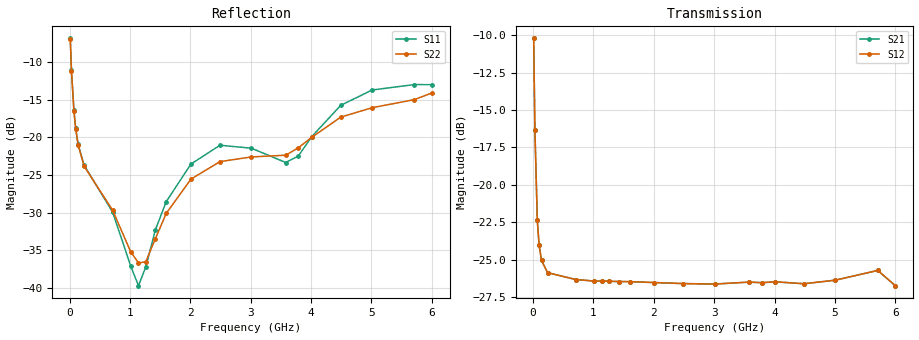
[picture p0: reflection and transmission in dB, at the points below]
! Integrated Device Technology
! Corporate Headquarters
! 6024 Silver Creek Valley Road
! San Jose, CA 95138  USA
! Phone:  1-408-284-8200
! Toll Free:  1-800-223-1366
! Webpage:  http://www.idt.com/
! Timing and RF Division
! 515 Groton Road, Suite 102
! Westford, MA 01886-6024
! Device:  F1951
! Description: 6-bit 0.5 dB Digital Step Attenuator
! Frequency:  100.0 -  4000.00 MHz
! Package:  4x4 mm Thin QFN Plastic Package: 24 pin
! Ports:  2 RF, 6 DC
!  Pin  1  = NC
!  Pin  2  = RF1  =  Port 1
!  Pin  3  = GND
!  Pin  4  = NC
!  Pin  5  = Serial Data Out (SDO)
!  Pin  6  = NC
!  Pin  7  = Reset Bar ( RSTb)
!  Pin  8  = Clock (CLK)
!  Pin  9  = Chip Select Bar (CSb)
!  Pin 10  = NC
!  Pin 11  = Serial Data In (SDI)
!  Pin 12  = NC
!  Pin 13  = NC
!  Pin 14  = VDD
!  Pin 15  = NC
!  Pin 16  = GND
!  Pin 17  = RF2  =  Port 2
!  Pin 18  = NC
!  Pin 19  = GND
!  Pin 20  = GND
!  Pin 21  = GND
!  Pin 22  = GND
!  Pin 23  = GND
!  Pin 24  = GND
! State:  51
! Atten State:  25.5 dB
! Voltage:  +3.30 Volts
! Current:  0.488 mA
! Data:  The device was measured on a F195X evaluation board which has
!  individual transmission lines to the RF pins.  Data was collected
!  de-embedded using a Automatic Fixture Removal [AFR] (Keysight Technologies).
!  The reference plane is the edge of the package pin.
! Misc:  Lot Code  1225BCA
!  Action Tracker AT0399
! Date Measured:  2018-09-13
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# GHz S dB R 50
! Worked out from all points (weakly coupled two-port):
!   600 points, 10 MHz to 6 GHz, reference 50 ohm
!   highest |S21| = -10.21 dB at 10 MHz (marker M1); lowest = -26.7 dB at 6 GHz (marker M2)
!   lowest |S11| = -39.7 dB at 1.14 GHz (marker M3), VSWR 1.02, Z = 49 + j0.169 ohm
!   |S11| at or under -10 dB: 24.23 MHz to end of sweep
!   |S22| runs from -37.1 to -6.9 dB; largest |S21 - S12| = 0.00016
!   S11 on the Smith chart (normalised r, x): 10 MHz: 1.80, -1.11; 30 MHz: 1.14, -0.60; 70 MHz: 0.97, -0.30; 1.26 GHz: 0.98, +0.02; 6 GHz: 0.80, +0.36
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0.01  -6.86 -32.7  -10.21 -35.5  -10.21 -35.5  -6.92 -32.8
0.03  -11.12 -61.4  -16.31 -54.9  -16.31 -54.9  -11.19 -61.5
0.07  -16.39 -86.3  -22.36 -46.9  -22.36 -46.9  -16.48 -86.6
0.1  -18.81 -96.9  -24.04 -38.3  -24.04 -38.2  -18.87 -97.2
0.14  -20.91 -107.1  -25.05 -30.4  -25.05 -30.3  -21.00 -107.0
0.24  -23.70 -121.2  -25.87 -20.7  -25.87 -20.7  -23.84 -121.5
0.71  -29.89 -133.2  -26.33 -14.8  -26.33 -14.8  -29.64 -137.0
1.01  -37.04 -151.4  -26.43 -16.5  -26.43 -16.5  -35.15 -151.2
1.14  -39.67 170.4  -26.44 -17.3  -26.44 -17.2  -36.65 -171.5
1.26  -37.21 133.4  -26.44 -18.2  -26.44 -18.2  -36.51 164.1
1.42  -32.26 117.2  -26.47 -19.8  -26.46 -19.8  -33.43 141.8
1.6  -28.51 114.7  -26.47 -21.4  -26.47 -21.4  -30.07 132.5
2.01  -23.53 123.3  -26.53 -25.7  -26.53 -25.7  -25.53 133.9
2.49  -21.04 136.7  -26.60 -30.6  -26.60 -30.6  -23.21 141.3
3.01  -21.43 147.1  -26.63 -35.7  -26.63 -35.7  -22.59 144.9
3.58  -23.33 126.1  -26.50 -41.3  -26.50 -41.3  -22.36 127.5
3.79  -22.45 110.1  -26.54 -43.4  -26.54 -43.4  -21.37 120.6
4.01  -19.90 101.3  -26.48 -45.7  -26.48 -45.6  -19.99 115.3
4.49  -15.75 99.6  -26.61 -50.0  -26.61 -50.0  -17.31 113.7
5.01  -13.71 108.5  -26.37 -52.7  -26.37 -52.7  -16.06 116.3
5.71  -12.99 113.6  -25.72 -63.8  -25.72 -63.8  -14.99 109.1
6  -13.00 107.5  -26.74 -65.7  -26.73 -65.7  -14.10 105.4
